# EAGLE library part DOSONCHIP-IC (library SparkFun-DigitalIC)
DOSonCHIP IC This is the tested schematic and footprint for the DOSonCHIP FAT16 FAT32 IC. Spark Fun Electronics SKU : COM-07956. QFN package also tested/proven.

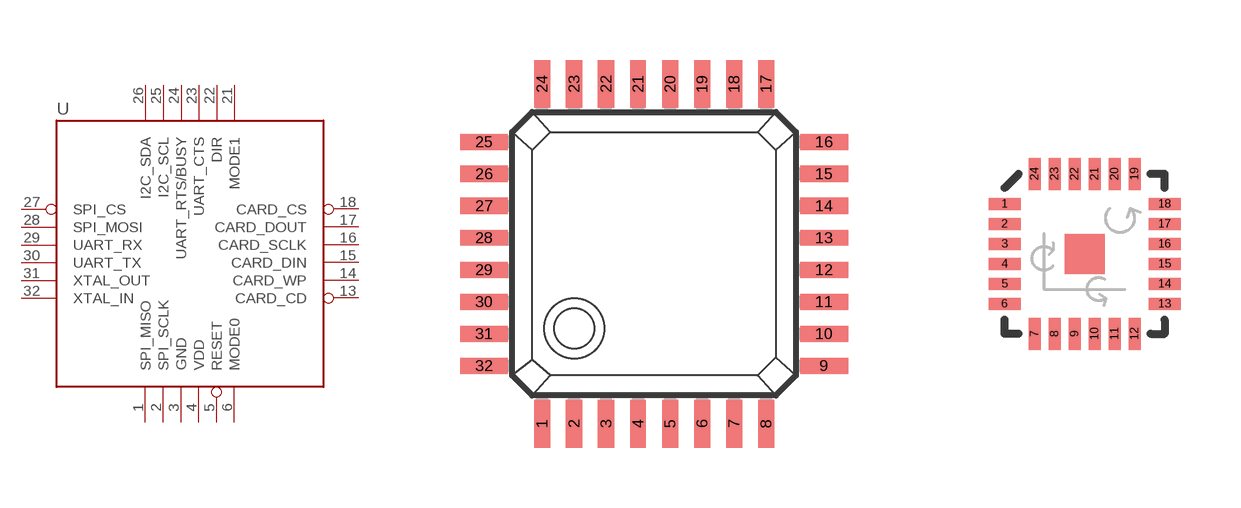
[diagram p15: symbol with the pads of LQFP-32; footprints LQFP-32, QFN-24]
Designator prefix -

## DOSONCHIP-ICLQFP  [LQFP-32]
1  SPI_MISO  out
2  SPI_SCLK  in
3  GND  in
4  VDD  in
5  RESET  in
6  MODE0  in
13  CARD_CD  in
14  CARD_WP  in
15  CARD_DIN
16  CARD_SCLK  out
17  CARD_DOUT  out
18  CARD_CS  in
21  MODE1  in
22  DIR  in
23  UART_CTS  in
24  UART_RTS/BUSY  out
25  I2C_SCL
26  I2C_SDA
27  SPI_CS  in
28  SPI_MOSI  in
29  UART_RX  in
30  UART_TX  out
31  XTAL_OUT  out
32  XTAL_IN  in

## DOSONCHIP-ICQFN  [QFN-24]
1  SPI_MISO  out
2  SPI_SCLK  in
3  GND  in
4  VDD  in
5  RESET  in
6  MODE0  in
7  CARD_CD  in
8  CARD_WP  in
9  CARD_DIN
10  CARD_SCLK  out
11  CARD_DOUT  out
12  CARD_CS  in
13  MODE1  in
14  DIR  in
15  UART_CTS  in
16  UART_RTS/BUSY  out
17  I2C_SCL
18  I2C_SDA
19  SPI_CS  in
20  SPI_MOSI  in
21  UART_RX  in
22  UART_TX  out
23  XTAL_OUT  out
24  XTAL_IN  in

## DOSONCHIP-ICQFN_ALT1  [QFN-24_ALT1.PAC]
Pads as for QFN-24

## Footprint LQFP-32 (pad centres in mm)
Quad Flat Package 32 LD LQFP Source: ds232b12.pdf http://www.ftdichip.com
smd 0.4 x 1.2: 1 -2.8,-4.25; 2 -2,-4.25; 3 -1.2,-4.25; 4 -0.4,-4.25; 5 0.4,-4.25; 6 1.2,-4.25; 7 2,-4.25; 8 2.8,-4.25; 17 2.8,4.25; 18 2,4.25; 19 1.2,4.25; 20 0.4,4.25; 21 -0.4,4.25; 22 -1.2,4.25; 23 -2,4.25; 24 -2.8,4.25
smd 1.2 x 0.4: 9 4.25,-2.8; 10 4.25,-2; 11 4.25,-1.2; 12 4.25,-0.4; 13 4.25,0.4; 14 4.25,1.2; 15 4.25,2; 16 4.25,2.8; 25 -4.25,2.8; 26 -4.25,2; 27 -4.25,1.2; 28 -4.25,0.4; 29 -4.25,-0.4; 30 -4.25,-1.2; 31 -4.25,-2; 32 -4.25,-2.8

## Footprint QFN-24 (pad centres in mm)
smd 0.8 x 0.3: 1 -2,1.25; 2 -2,0.75; 3 -2,0.25; 4 -2,-0.25; 5 -2,-0.75; 6 -2,-1.25; 13 2,-1.25; 14 2,-0.75; 15 2,-0.25; 16 2,0.25; 17 2,0.75; 18 2,1.25
smd 0.3 x 0.8: 7 -1.25,-2; 8 -0.75,-2; 9 -0.25,-2; 10 0.25,-2; 11 0.75,-2; 12 1.25,-2; 19 1.25,2; 20 0.75,2; 21 0.25,2; 22 -0.25,2; 23 -0.75,2; 24 -1.25,2

## Footprint QFN-24_ALT1.PAC (pad centres in mm)
smd 0.851 x 0.3: 1 -2.025,1.25; 2 -2.025,0.75; 3 -2.025,0.25; 4 -2.025,-0.25; 5 -2.025,-0.75; 6 -2.025,-1.25; 13 2.025,-1.25; 14 2.025,-0.75; 15 2.025,-0.25; 16 2.025,0.25; 17 2.025,0.75; 18 2.025,1.25
smd 0.3 x 0.851: 7 -1.25,-2.025; 8 -0.75,-2.025; 9 -0.25,-2.025; 10 0.25,-2.025; 11 0.75,-2.025; 12 1.25,-2.025; 19 1.25,2.025; 20 0.75,2.025; 21 0.25,2.025; 22 -0.25,2.025; 23 -0.75,2.025; 24 -1.25,2.025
